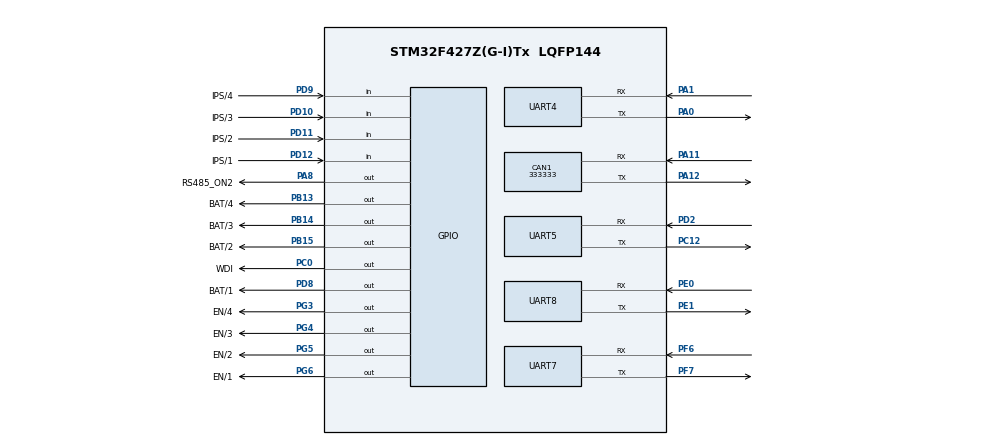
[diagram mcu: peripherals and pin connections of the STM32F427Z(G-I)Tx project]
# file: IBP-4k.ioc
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CAN1.CalculateBaudRate=333333
CAN1.CalculateTimeBit=3000
CAN1.CalculateTimeQuantum=1000.0
Dma.Request0=UART8_RX
Dma.Request1=UART8_TX
Dma.Request2=UART4_RX
Dma.Request3=UART4_TX
Dma.Request4=UART7_RX
Dma.Request5=UART7_TX
Dma.UART4_RX.2.Direction=DMA_PERIPH_TO_MEMORY
Dma.UART4_RX.2.FIFOMode=DMA_FIFOMODE_DISABLE
Dma.UART4_RX.2.Instance=DMA1_Stream2
Dma.UART4_RX.2.MemDataAlignment=DMA_MDATAALIGN_BYTE
Dma.UART4_RX.2.MemInc=DMA_MINC_ENABLE
Dma.UART4_RX.2.Mode=DMA_NORMAL
Dma.UART4_RX.2.PeriphDataAlignment=DMA_PDATAALIGN_BYTE
Dma.UART4_RX.2.PeriphInc=DMA_PINC_DISABLE
Dma.UART4_RX.2.Priority=DMA_PRIORITY_LOW
Dma.UART4_TX.3.Direction=DMA_MEMORY_TO_PERIPH
Dma.UART4_TX.3.FIFOMode=DMA_FIFOMODE_DISABLE
Dma.UART4_TX.3.Instance=DMA1_Stream4
Dma.UART4_TX.3.MemDataAlignment=DMA_MDATAALIGN_BYTE
Dma.UART4_TX.3.MemInc=DMA_MINC_ENABLE
Dma.UART4_TX.3.Mode=DMA_NORMAL
Dma.UART4_TX.3.PeriphDataAlignment=DMA_PDATAALIGN_BYTE
Dma.UART4_TX.3.PeriphInc=DMA_PINC_DISABLE
Dma.UART4_TX.3.Priority=DMA_PRIORITY_LOW
Dma.UART7_RX.4.Direction=DMA_PERIPH_TO_MEMORY
Dma.UART7_RX.4.FIFOMode=DMA_FIFOMODE_DISABLE
Dma.UART7_RX.4.Instance=DMA1_Stream3
Dma.UART7_RX.4.MemDataAlignment=DMA_MDATAALIGN_BYTE
Dma.UART7_RX.4.MemInc=DMA_MINC_ENABLE
Dma.UART7_RX.4.Mode=DMA_NORMAL
Dma.UART7_RX.4.PeriphDataAlignment=DMA_PDATAALIGN_BYTE
Dma.UART7_RX.4.PeriphInc=DMA_PINC_DISABLE
Dma.UART7_RX.4.Priority=DMA_PRIORITY_LOW
Dma.UART7_TX.5.Direction=DMA_MEMORY_TO_PERIPH
Dma.UART7_TX.5.FIFOMode=DMA_FIFOMODE_DISABLE
Dma.UART7_TX.5.Instance=DMA1_Stream1
Dma.UART7_TX.5.MemDataAlignment=DMA_MDATAALIGN_BYTE
Dma.UART7_TX.5.MemInc=DMA_MINC_ENABLE
Dma.UART7_TX.5.Mode=DMA_NORMAL
Dma.UART7_TX.5.PeriphDataAlignment=DMA_PDATAALIGN_BYTE
Dma.UART7_TX.5.PeriphInc=DMA_PINC_DISABLE
Dma.UART7_TX.5.Priority=DMA_PRIORITY_LOW
Dma.UART8_RX.0.Direction=DMA_PERIPH_TO_MEMORY
Dma.UART8_RX.0.FIFOMode=DMA_FIFOMODE_DISABLE
Dma.UART8_RX.0.Instance=DMA1_Stream6
Dma.UART8_RX.0.MemDataAlignment=DMA_MDATAALIGN_BYTE
Dma.UART8_RX.0.MemInc=DMA_MINC_ENABLE
Dma.UART8_RX.0.Mode=DMA_NORMAL
Dma.UART8_RX.0.PeriphDataAlignment=DMA_PDATAALIGN_BYTE
Dma.UART8_RX.0.PeriphInc=DMA_PINC_DISABLE
Dma.UART8_RX.0.Priority=DMA_PRIORITY_LOW
Dma.UART8_TX.1.Direction=DMA_MEMORY_TO_PERIPH
Dma.UART8_TX.1.FIFOMode=DMA_FIFOMODE_DISABLE
Dma.UART8_TX.1.Instance=DMA1_Stream0
Dma.UART8_TX.1.MemDataAlignment=DMA_MDATAALIGN_BYTE
Dma.UART8_TX.1.MemInc=DMA_MINC_ENABLE
Dma.UART8_TX.1.Mode=DMA_NORMAL
Dma.UART8_TX.1.PeriphDataAlignment=DMA_PDATAALIGN_BYTE
Dma.UART8_TX.1.PeriphInc=DMA_PINC_DISABLE
Dma.UART8_TX.1.Priority=DMA_PRIORITY_LOW
FREERTOS.Tasks01=defaultTask,0,1280,StartDefaultTask,Default,NULL,Dynamic,NULL,NULL;myTask02,-3,1280,StartTask02,Default,NULL,Dynamic,NULL,NULL;WDI_Task,-3,128,StartTask03,Default,NULL,Dynamic,NULL,NULL
Mcu.Family=STM32F4
Mcu.Name=STM32F427Z(G-I)Tx
Mcu.Package=LQFP144
NVIC.CAN1_RX0_IRQn=true\:5\:0\:false\:false\:true\:true\:false\:true\:true
NVIC.CAN1_SCE_IRQn=true\:5\:0\:false\:false\:true\:true\:false\:true\:true
NVIC.CAN1_TX_IRQn=true\:5\:0\:false\:false\:true\:true\:false\:true\:true
NVIC.DMA1_Stream0_IRQn=true\:5\:0\:false\:false\:true\:true\:false\:true\:true
NVIC.DMA1_Stream1_IRQn=true\:5\:0\:false\:false\:true\:true\:false\:true\:true
NVIC.DMA1_Stream2_IRQn=true\:5\:0\:false\:false\:true\:true\:false\:true\:true
NVIC.DMA1_Stream3_IRQn=true\:5\:0\:false\:false\:true\:true\:false\:true\:true
NVIC.DMA1_Stream4_IRQn=true\:5\:0\:false\:false\:true\:true\:false\:true\:true
NVIC.DMA1_Stream6_IRQn=true\:5\:0\:false\:false\:true\:true\:false\:true\:true
NVIC.PriorityGroup=NVIC_PRIORITYGROUP_4
NVIC.TIM1_UP_TIM10_IRQn=true\:15\:0\:false\:false\:true\:false\:false\:true\:true
NVIC.TimeBase=TIM1_UP_TIM10_IRQn
NVIC.TimeBaseIP=TIM1
NVIC.UART4_IRQn=true\:5\:0\:false\:false\:true\:true\:false\:true\:true
NVIC.UART5_IRQn=true\:5\:0\:false\:false\:true\:true\:true\:true\:true
NVIC.UART7_IRQn=true\:5\:0\:false\:false\:true\:true\:true\:true\:true
NVIC.UART8_IRQn=true\:5\:0\:false\:false\:true\:true\:true\:true\:true
PA0/WKUP.Mode=Asynchronous
PA0/WKUP.Signal=UART4_TX
PA1.Mode=Asynchronous
PA1.Signal=UART4_RX
PA11.Mode=CAN_Activate
PA11.Signal=CAN1_RX
PA12.Mode=CAN_Activate
PA12.Signal=CAN1_TX
PA13.Mode=JTAG_5_pins
PA13.Signal=SYS_JTMS-SWDIO
PA14.Mode=JTAG_5_pins
PA14.Signal=SYS_JTCK-SWCLK
PA15.Mode=JTAG_5_pins
PA15.Signal=SYS_JTDI
PA8.GPIO_Label=RS485_ON2
PA8.Signal=GPIO_Output
PB13.GPIO_Label=BAT/4
PB13.Signal=GPIO_Output
PB14.GPIO_Label=BAT/3
PB14.Signal=GPIO_Output
PB15.GPIO_Label=BAT/2
PB15.Signal=GPIO_Output
PB3.Mode=JTAG_5_pins
PB3.Signal=SYS_JTDO-SWO
PB4.Mode=JTAG_5_pins
PB4.Signal=SYS_JTRST
PC0.GPIO_Label=WDI
PC0.Signal=GPIO_Output
PC12.Mode=Asynchronous
PC12.Signal=UART5_TX
PD2.Mode=Asynchronous
PD2.Signal=UART5_RX
PD8.GPIO_Label=BAT/1
PD8.Signal=GPIO_Output
PD9.GPIO_Label=IPS/4
PD9.Signal=GPIO_Input
PD10.GPIO_Label=IPS/3
PD10.Signal=GPIO_Input
PD11.GPIO_Label=IPS/2
PD11.Signal=GPIO_Input
PD12.GPIO_Label=IPS/1
PD12.Signal=GPIO_Input
PE0.Mode=Asynchronous
PE0.Signal=UART8_RX
PE1.Mode=Asynchronous
PE1.Signal=UART8_TX
PF6.Mode=Asynchronous
PF6.Signal=UART7_RX
PF7.Mode=Asynchronous
PF7.Signal=UART7_TX
PG3.GPIO_Label=EN/4
PG3.Signal=GPIO_Output
PG4.GPIO_Label=EN/3
PG4.Signal=GPIO_Output
PG5.GPIO_Label=EN/2
PG5.Signal=GPIO_Output
PG6.GPIO_Label=EN/1
PG6.Signal=GPIO_Output
PH0/OSC_IN.Signal=RCC_OSC_IN
PH1/OSC_OUT.Signal=RCC_OSC_OUT
ProjectManager.HeapSize=0x200
ProjectManager.StackSize=0x400
ProjectManager.TargetToolchain=EWARM V8.50
RCC.AHBFreq_Value=16000000
RCC.APB1Freq_Value=16000000
RCC.APB2Freq_Value=16000000
RCC.CortexFreq_Value=16000000
RCC.HSE_VALUE=25000000
RCC.HSI_VALUE=16000000
RCC.LSE_VALUE=32768
RCC.SYSCLKFreq_VALUE=16000000
RCC.VCOOutputFreq_Value=192000000
UART4.VirtualMode=Asynchronous
UART5.VirtualMode=Asynchronous
UART7.VirtualMode=Asynchronous
UART8.VirtualMode=Asynchronous
VP_FREERTOS_VS_CMSIS_V1.Mode=CMSIS_V1
VP_SYS_VS_tim1.Mode=TIM1
board=custom

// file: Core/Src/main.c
/* USER CODE BEGIN Header */
/**
  ******************************************************************************
  * @file           : main.c
  * @brief          : Main program body
  ******************************************************************************
  * @attention
  *
  * Copyright (c) 2025 STMicroelectronics.
  * All rights reserved.
  *
  * This software is licensed under terms that can be found in the LICENSE file
  * in the root directory of this software component.
  * If no LICENSE file comes with this software, it is provided AS-IS.
  *
  ******************************************************************************
  */
/* USER CODE END Header */
#include "main.h"
#include "cmsis_os.h"

/* USER CODE BEGIN Includes */
#include "app_config.h"
#include "battery_modbus.h"
#include "can.h"
#include "can_service.h"
#include "firmware_update.h"
#include "slave_update_thread.h"
#include "supervision.h"
#include "uart.h"
/* USER CODE END Includes */

CAN_HandleTypeDef hcan1;

UART_HandleTypeDef huart4;
UART_HandleTypeDef huart5;
UART_HandleTypeDef huart7;
UART_HandleTypeDef huart8;
DMA_HandleTypeDef hdma_uart4_rx;
DMA_HandleTypeDef hdma_uart4_tx;
DMA_HandleTypeDef hdma_uart7_rx;
DMA_HandleTypeDef hdma_uart7_tx;
DMA_HandleTypeDef hdma_uart8_rx;
DMA_HandleTypeDef hdma_uart8_tx;

osThreadId defaultTaskHandle;
osThreadId myTask02Handle;
osThreadId WDI_TaskHandle;
osThreadId myTask04Handle;

void SystemClock_Config(void);
static void MX_GPIO_Init(void);
static void MX_DMA_Init(void);
void StartDefaultTask(void const * argument);
void StartTask02(void const * argument);
void StartTask03(void const * argument);
void StartTask04(void const * argument);

/* USER CODE BEGIN 0 */

/**
  * @brief  Точка входа приложения: инициализирует HAL, периферию и задачи RTOS.
  * @retval Код возврата, фактически не используется после запуска scheduler.
  */
int main(void)
{
  /* USER CODE BEGIN 1 */
    // === Установка вектора прерываний приложения ===
    // SystemInit() может уже это делать, но лучше явно
    SCB->VTOR = FLASH_APP_START_ADDR;

    // Включить прерывания (если были выключены в bootloader)
    __enable_irq();
  /* USER CODE END 1 */

  /* MCU Configuration--------------------------------------------------------*/

  /* Reset of all peripherals, Initializes the Flash interface and the Systick. */
  HAL_Init();

  /* USER CODE BEGIN Init */
  FW_LoadStoredImageInfo();

  /* USER CODE END Init */

  /* Configure the system clock */
  SystemClock_Config();

  /* Initialize all configured peripherals */
  MX_GPIO_Init();
  MX_DMA_Init();

#if UARTS_ENABLE == 1
  MX_UART8_Init();
  MX_UART5_Init();
  MX_UART4_Init();
  MX_UART7_Init();
#endif

#if CAN_ENABLE == 1
  MX_CAN1_Init();
#endif

  /* USER CODE BEGIN 2 */

  /* Инициализируем UART-контексты и прием до запуска scheduler. */
  HAL_Delay(100);
  UART_Init();
  HAL_Delay(100);
  UART_StartAllReceptions();

  /* USER CODE END 2 */

//#if CAN_ENABLE == 1
//  MX_CAN1_Init();
//#endif
  /*
    static uint8_t test_logged = 0u;

    if (test_logged == 0u)
    {
        test_logged = 1u;
        CAN_ReportFlashWriteError();
    }
*/
  /* Create the thread(s) */
  /* definition and creation of defaultTask */
  osThreadDef(defaultTask, StartDefaultTask, osPriorityNormal, 0, 1280); //1280
  defaultTaskHandle = osThreadCreate(osThread(defaultTask), NULL);

  /* definition and creation of myTask02 */
  osThreadDef(myTask02, StartTask02, osPriorityIdle, 0, 1280);
  myTask02Handle = osThreadCreate(osThread(myTask02), NULL);

  /* definition and creation of WDI_Task */
  osThreadDef(WDI_Task, StartTask03, osPriorityIdle, 0, 128);
  WDI_TaskHandle = osThreadCreate(osThread(WDI_Task), NULL);

  /* USER CODE BEGIN RTOS_THREADS */
  osThreadDef(myTask04, StartTask04, osPriorityIdle, 0, 512);
  myTask04Handle = osThreadCreate(osThread(myTask04), NULL);
  /* USER CODE END RTOS_THREADS */

  /* Start scheduler */
  osKernelStart();

  /* We should never get here as control is now taken by the scheduler */

  /* Infinite loop */
  while (1)
  {

  }
}

/**
  * @brief Настраивает системное тактирование MCU от HSE через PLL.
  * @retval Нет.
  */
void SystemClock_Config(void)
{
  RCC_OscInitTypeDef RCC_OscInitStruct = {0};
  RCC_ClkInitTypeDef RCC_ClkInitStruct = {0};

  __HAL_RCC_PWR_CLK_ENABLE();
  __HAL_PWR_VOLTAGESCALING_CONFIG(PWR_REGULATOR_VOLTAGE_SCALE1);

  RCC_OscInitStruct.OscillatorType = RCC_OSCILLATORTYPE_HSE;
  RCC_OscInitStruct.HSEState = RCC_HSE_ON;
  RCC_OscInitStruct.PLL.PLLState = RCC_PLL_ON;
  RCC_OscInitStruct.PLL.PLLSource = RCC_PLLSOURCE_HSE;
  RCC_OscInitStruct.PLL.PLLM = 6;
  RCC_OscInitStruct.PLL.PLLN = 180;
  RCC_OscInitStruct.PLL.PLLP = RCC_PLLP_DIV4;  //RCC_PLLP_DIV2 = 180
  RCC_OscInitStruct.PLL.PLLQ = 4;
  if (HAL_RCC_OscConfig(&RCC_OscInitStruct) != HAL_OK)
  {
    Error_Handler();
  }

  if (HAL_PWREx_EnableOverDrive() != HAL_OK)
  {
    Error_Handler();
  }

  RCC_ClkInitStruct.ClockType = RCC_CLOCKTYPE_HCLK|RCC_CLOCKTYPE_SYSCLK
                                |RCC_CLOCKTYPE_PCLK1|RCC_CLOCKTYPE_PCLK2;
  RCC_ClkInitStruct.SYSCLKSource = RCC_SYSCLKSOURCE_PLLCLK;
  RCC_ClkInitStruct.AHBCLKDivider = RCC_SYSCLK_DIV1;
  RCC_ClkInitStruct.APB1CLKDivider = RCC_HCLK_DIV4;
  RCC_ClkInitStruct.APB2CLKDivider = RCC_HCLK_DIV2;
  if (HAL_RCC_ClockConfig(&RCC_ClkInitStruct, FLASH_LATENCY_5) != HAL_OK)
  {
    Error_Handler();
  }
}

/**
  * @brief Включает тактирование DMA и настраивает прерывания DMA-потоков UART.
  */
static void MX_DMA_Init(void)
{
  /* DMA controller clock enable */
  __HAL_RCC_DMA1_CLK_ENABLE();

  /* DMA interrupt init */
  /* DMA1_Stream0_IRQn interrupt configuration */
  HAL_NVIC_SetPriority(DMA1_Stream0_IRQn, 5, 0);
  HAL_NVIC_EnableIRQ(DMA1_Stream0_IRQn);
  /* DMA1_Stream1_IRQn interrupt configuration */
  HAL_NVIC_SetPriority(DMA1_Stream1_IRQn, 5, 0);
  HAL_NVIC_EnableIRQ(DMA1_Stream1_IRQn);
  /* DMA1_Stream2_IRQn interrupt configuration */
  HAL_NVIC_SetPriority(DMA1_Stream2_IRQn, 5, 0);
  HAL_NVIC_EnableIRQ(DMA1_Stream2_IRQn);
  /* DMA1_Stream3_IRQn interrupt configuration */
  HAL_NVIC_SetPriority(DMA1_Stream3_IRQn, 5, 0);
  HAL_NVIC_EnableIRQ(DMA1_Stream3_IRQn);
  /* DMA1_Stream4_IRQn interrupt configuration */
  HAL_NVIC_SetPriority(DMA1_Stream4_IRQn, 5, 0);
  HAL_NVIC_EnableIRQ(DMA1_Stream4_IRQn);
  /* DMA1_Stream6_IRQn interrupt configuration */
  HAL_NVIC_SetPriority(DMA1_Stream6_IRQn, 5, 0);
  HAL_NVIC_EnableIRQ(DMA1_Stream6_IRQn);
}

/**
  * @brief Инициализирует GPIO входы и выходы платы.
  * @param Нет.
  * @retval Нет.
  */
static void MX_GPIO_Init(void)
{
  GPIO_InitTypeDef GPIO_InitStruct = {0};

  /* GPIO Ports Clock Enable */
  __HAL_RCC_GPIOF_CLK_ENABLE();
  __HAL_RCC_GPIOH_CLK_ENABLE();
  __HAL_RCC_GPIOC_CLK_ENABLE();
  __HAL_RCC_GPIOA_CLK_ENABLE();
  __HAL_RCC_GPIOB_CLK_ENABLE();
  __HAL_RCC_GPIOD_CLK_ENABLE();
  __HAL_RCC_GPIOG_CLK_ENABLE();
  __HAL_RCC_GPIOE_CLK_ENABLE();

  /*Configure GPIO pin Output Level */
  HAL_GPIO_WritePin(WDI_GPIO_Port, WDI_Pin, GPIO_PIN_RESET);

  /*Configure GPIO pin Output Level */
  HAL_GPIO_WritePin(GPIOB, BAT_4_Pin|BAT_3_Pin|BAT_2_Pin, GPIO_PIN_RESET);

  /*Configure GPIO pin Output Level */
  HAL_GPIO_WritePin(BAT_1_GPIO_Port, BAT_1_Pin, GPIO_PIN_RESET);

  /*Configure GPIO pin Output Level */
  HAL_GPIO_WritePin(GPIOG, EN_4_Pin|EN_3_Pin|EN_2_Pin|EN_1_Pin, GPIO_PIN_RESET);

  /*Configure GPIO pin Output Level */
  HAL_GPIO_WritePin(RS485_ON2_GPIO_Port, RS485_ON2_Pin, GPIO_PIN_RESET);

  /*Configure GPIO pin : WDI_Pin */
  GPIO_InitStruct.Pin = WDI_Pin;
  GPIO_InitStruct.Mode = GPIO_MODE_OUTPUT_PP;
  GPIO_InitStruct.Pull = GPIO_NOPULL;
  GPIO_InitStruct.Speed = GPIO_SPEED_FREQ_LOW;
  HAL_GPIO_Init(WDI_GPIO_Port, &GPIO_InitStruct);

  /*Configure GPIO pins : BAT_4_Pin BAT_3_Pin BAT_2_Pin */
  GPIO_InitStruct.Pin = BAT_4_Pin|BAT_3_Pin|BAT_2_Pin;
  GPIO_InitStruct.Mode = GPIO_MODE_OUTPUT_PP;
  GPIO_InitStruct.Pull = GPIO_NOPULL;
  GPIO_InitStruct.Speed = GPIO_SPEED_FREQ_LOW;
  HAL_GPIO_Init(GPIOB, &GPIO_InitStruct);

  /*Configure GPIO pin : BAT_1_Pin */
  GPIO_InitStruct.Pin = BAT_1_Pin;
  GPIO_InitStruct.Mode = GPIO_MODE_OUTPUT_PP;
  GPIO_InitStruct.Pull = GPIO_NOPULL;
  GPIO_InitStruct.Speed = GPIO_SPEED_FREQ_LOW;
  HAL_GPIO_Init(BAT_1_GPIO_Port, &GPIO_InitStruct);

  /*Configure GPIO pins : IPS_4_Pin IPS_3_Pin IPS_2_Pin IPS_1_Pin */
  GPIO_InitStruct.Pin = IPS_4_Pin|IPS_3_Pin|IPS_2_Pin|IPS_1_Pin;
  GPIO_InitStruct.Mode = GPIO_MODE_INPUT;
  GPIO_InitStruct.Pull = GPIO_NOPULL;
  HAL_GPIO_Init(GPIOD, &GPIO_InitStruct);

  /*Configure GPIO pins : EN_4_Pin EN_3_Pin EN_2_Pin EN_1_Pin */
  GPIO_InitStruct.Pin = EN_4_Pin|EN_3_Pin|EN_2_Pin|EN_1_Pin;
  GPIO_InitStruct.Mode = GPIO_MODE_OUTPUT_PP;
  GPIO_InitStruct.Pull = GPIO_NOPULL;
  GPIO_InitStruct.Speed = GPIO_SPEED_FREQ_LOW;
  HAL_GPIO_Init(GPIOG, &GPIO_InitStruct);

  /*Configure GPIO pin : RS485_ON2_Pin */
  GPIO_InitStruct.Pin = RS485_ON2_Pin;
  GPIO_InitStruct.Mode = GPIO_MODE_OUTPUT_PP;
  GPIO_InitStruct.Pull = GPIO_NOPULL;
  GPIO_InitStruct.Speed = GPIO_SPEED_FREQ_LOW;
  HAL_GPIO_Init(RS485_ON2_GPIO_Port, &GPIO_InitStruct);
}

/* USER CODE BEGIN Header_StartDefaultTask */
/**
  * @brief  Обертка FreeRTOS-задачи CAN-сервиса.
  * @param  argument Аргумент задачи, не используется.
  * @retval Нет.
  */
/* USER CODE END Header_StartDefaultTask */
void StartDefaultTask(void const * argument)
{
  /* USER CODE BEGIN 5 */
  /* Передает управление сервису CAN, чтобы main.c не владел протокольной логикой. */
  CanService_Task(argument);
  /* USER CODE END 5 */
}

/* USER CODE BEGIN Header_StartTask02 */
/**
* @brief Обертка FreeRTOS-задачи UART/Modbus-опроса батарей.
* @param argument Аргумент задачи, не используется.
* @retval Нет.
*/
/* USER CODE END Header_StartTask02 */
void StartTask02(void const * argument)
{
  /* USER CODE BEGIN StartTask02 */
  /* Передает управление сервису Modbus-опроса батарейных блоков. */
#if UARTS_ENABLE == 1
  UART_CreateMutexes();
#endif
  BatteryModbus_Task(argument);
  /* USER CODE END StartTask02 */
}

/* USER CODE BEGIN Header_StartTask03 */
/**
* @brief Обертка FreeRTOS-задачи watchdog, IPS-входов и таймаутов связи.
* @param argument Аргумент задачи, не используется.
* @retval Нет.
*/
/* USER CODE END Header_StartTask03 */
void StartTask03(void const * argument)
{
  /* USER CODE BEGIN StartTask03 */
  /* Передает управление сервису watchdog, IPS-входов и таймаутов связи. */
  Supervision_Task(argument);
  /* USER CODE END StartTask03 */
}

/* USER CODE BEGIN Header_StartTask04 */
/**
* @brief Обертка FreeRTOS-задачи фоновой прошивки ведомых контроллеров.
* @param argument Аргумент задачи, не используется.
* @retval Нет.
*/
/* USER CODE END Header_StartTask04 */
void StartTask04(void const * argument)
{
  /* USER CODE BEGIN StartTask04 */
  /* Передает управление фоновой задаче прошивки ведомых контроллеров. */
  Slave_UpdateTask(argument);
  /* USER CODE END StartTask04 */
}

/**
  * @brief  Обрабатывает периодическое прерывание таймера системного времени HAL.
  * @param  htim Указатель на handle таймера.
  * @retval Нет.
  */
void HAL_TIM_PeriodElapsedCallback(TIM_HandleTypeDef *htim)
{
  if (htim->Instance == TIM1)
  {
    HAL_IncTick();
  }
}

/**
  * @brief  Останавливает приложение при критической ошибке и запрещает прерывания.
  * @retval Нет.
  */
void Error_Handler(void)
{
  __disable_irq();
  while (1)
  {
  }
}

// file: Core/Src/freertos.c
/* USER CODE BEGIN Header */
/**
  ******************************************************************************
  * File Name          : freertos.c
  * Description        : Code for freertos applications
  ******************************************************************************
  * @attention
  *
  * Copyright (c) 2025 STMicroelectronics.
  * All rights reserved.
  *
  * This software is licensed under terms that can be found in the LICENSE file
  * in the root directory of this software component.
  * If no LICENSE file comes with this software, it is provided AS-IS.
  *
  ******************************************************************************
  */
/* USER CODE END Header */

#include "FreeRTOS.h"
#include "task.h"
#include "main.h"

/* GetIdleTaskMemory prototype (linked to static allocation support) */
void vApplicationGetIdleTaskMemory( StaticTask_t **ppxIdleTaskTCBBuffer, StackType_t **ppxIdleTaskStackBuffer, uint32_t *pulIdleTaskStackSize );

/* USER CODE BEGIN GET_IDLE_TASK_MEMORY */
static StaticTask_t xIdleTaskTCBBuffer;
static StackType_t xIdleStack[configMINIMAL_STACK_SIZE];

void vApplicationGetIdleTaskMemory( StaticTask_t **ppxIdleTaskTCBBuffer, StackType_t **ppxIdleTaskStackBuffer, uint32_t *pulIdleTaskStackSize )
{
  *ppxIdleTaskTCBBuffer = &xIdleTaskTCBBuffer;
  *ppxIdleTaskStackBuffer = &xIdleStack[0];
  *pulIdleTaskStackSize = configMINIMAL_STACK_SIZE;
  /* place for user code */
}
/* USER CODE END GET_IDLE_TASK_MEMORY */

/* USER CODE BEGIN Application */

/* Функция-хук FreeRTOS для отслеживания переполнения стека */
void vApplicationStackOverflowHook(TaskHandle_t xTask, char *pcTaskName)
{
  /* Комментарий: фиксируем имя задачи с переполнением стека */
  (void)xTask;
  (void)pcTaskName;
  Error_Handler();
}

/* Функция-хук FreeRTOS для отслеживания ошибок выделения памяти */
void vApplicationMallocFailedHook(void)
{
  /* Комментарий: фиксируем ошибку выделения памяти из кучи */
  Error_Handler();
}

/* USER CODE END Application */
